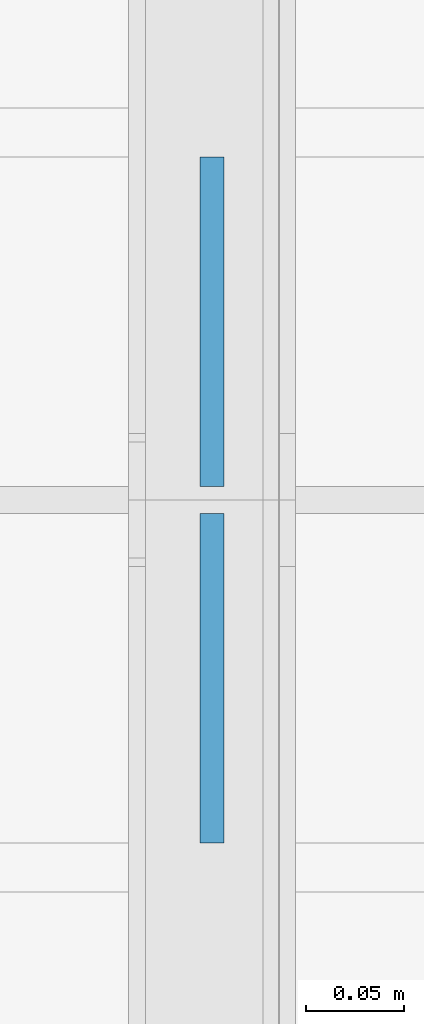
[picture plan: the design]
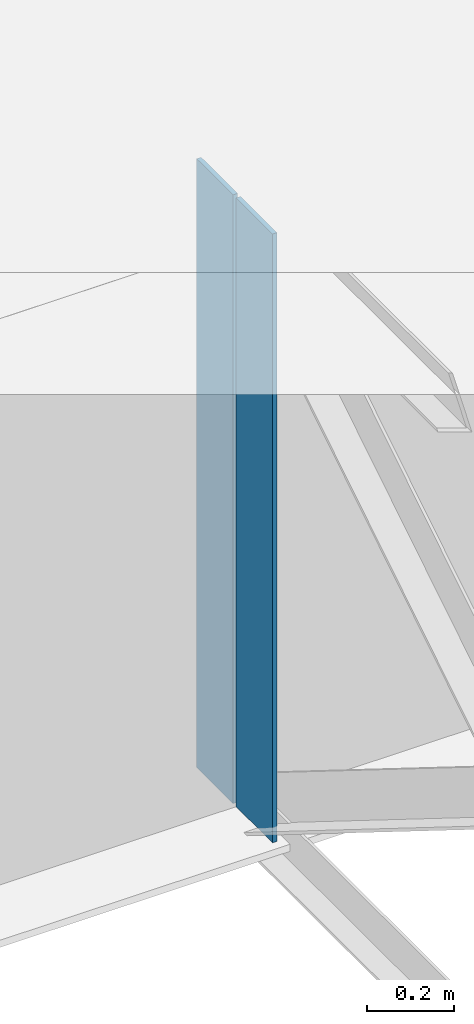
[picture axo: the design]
# One storey, part 9 of 17: 2 plates.
"""IFC4 building model written with IfcOpenShell, lengths in metres."""

from ifc_helpers import new_model, si_unit, frame, origin, origin_with_axes, origin_2d_with_axis, place, context, subcontext, project, spatial, rectangle, extrude, element, save


model = new_model("IFC4")

# Units and contexts
model_context = context("Model", 3, precision=1e-05, world=origin())
body_context = subcontext(model_context, "Body", "Model", "MODEL_VIEW")
ifc_project = project(units=[si_unit("LENGTHUNIT", "METRE"), si_unit("AREAUNIT", "SQUARE_METRE"), si_unit("VOLUMEUNIT", "CUBIC_METRE"), si_unit("PLANEANGLEUNIT", "RADIAN")], contexts=[model_context])

# Site, building, storey
site_placement = place(None, origin_with_axes())
site = spatial("IfcSite", under=ifc_project, at=site_placement)
building_placement = place(site_placement, origin_with_axes())
building = spatial("IfcBuilding", under=site, at=building_placement, Name="Bridge Structure")
storey_placement = place(building_placement, origin_with_axes())
storey = spatial("IfcBuildingStorey", under=building, at=storey_placement, Name="Superstructure")

# Plates
for number, where, z_axis, x_axis, name in (
    (1, (15.0, 0.091, -0.857), (0.0, 0.0, 1.0), (1.0, 0.0, 0.0), "Intermediate Stiffener 3"),
    (2, (15.0, -0.091, -0.857), (0.0, 0.0, 1.0), (1.0, 0.0, 0.0), "Intermediate Stiffener 3"),
):
    element("IfcPlate", number, at=place(storey_placement, frame(where, z_axis=z_axis, x_axis=x_axis)), inside=storey, Name=name, context=body_context, shape_type="SweptSolid", body=[
        extrude(rectangle(XDim=0.012, YDim=0.168, at=origin_2d_with_axis()), origin_with_axes(), (0.0, 0.0, 1.0), 1.714),
    ])

save(model, "model.ifc")
